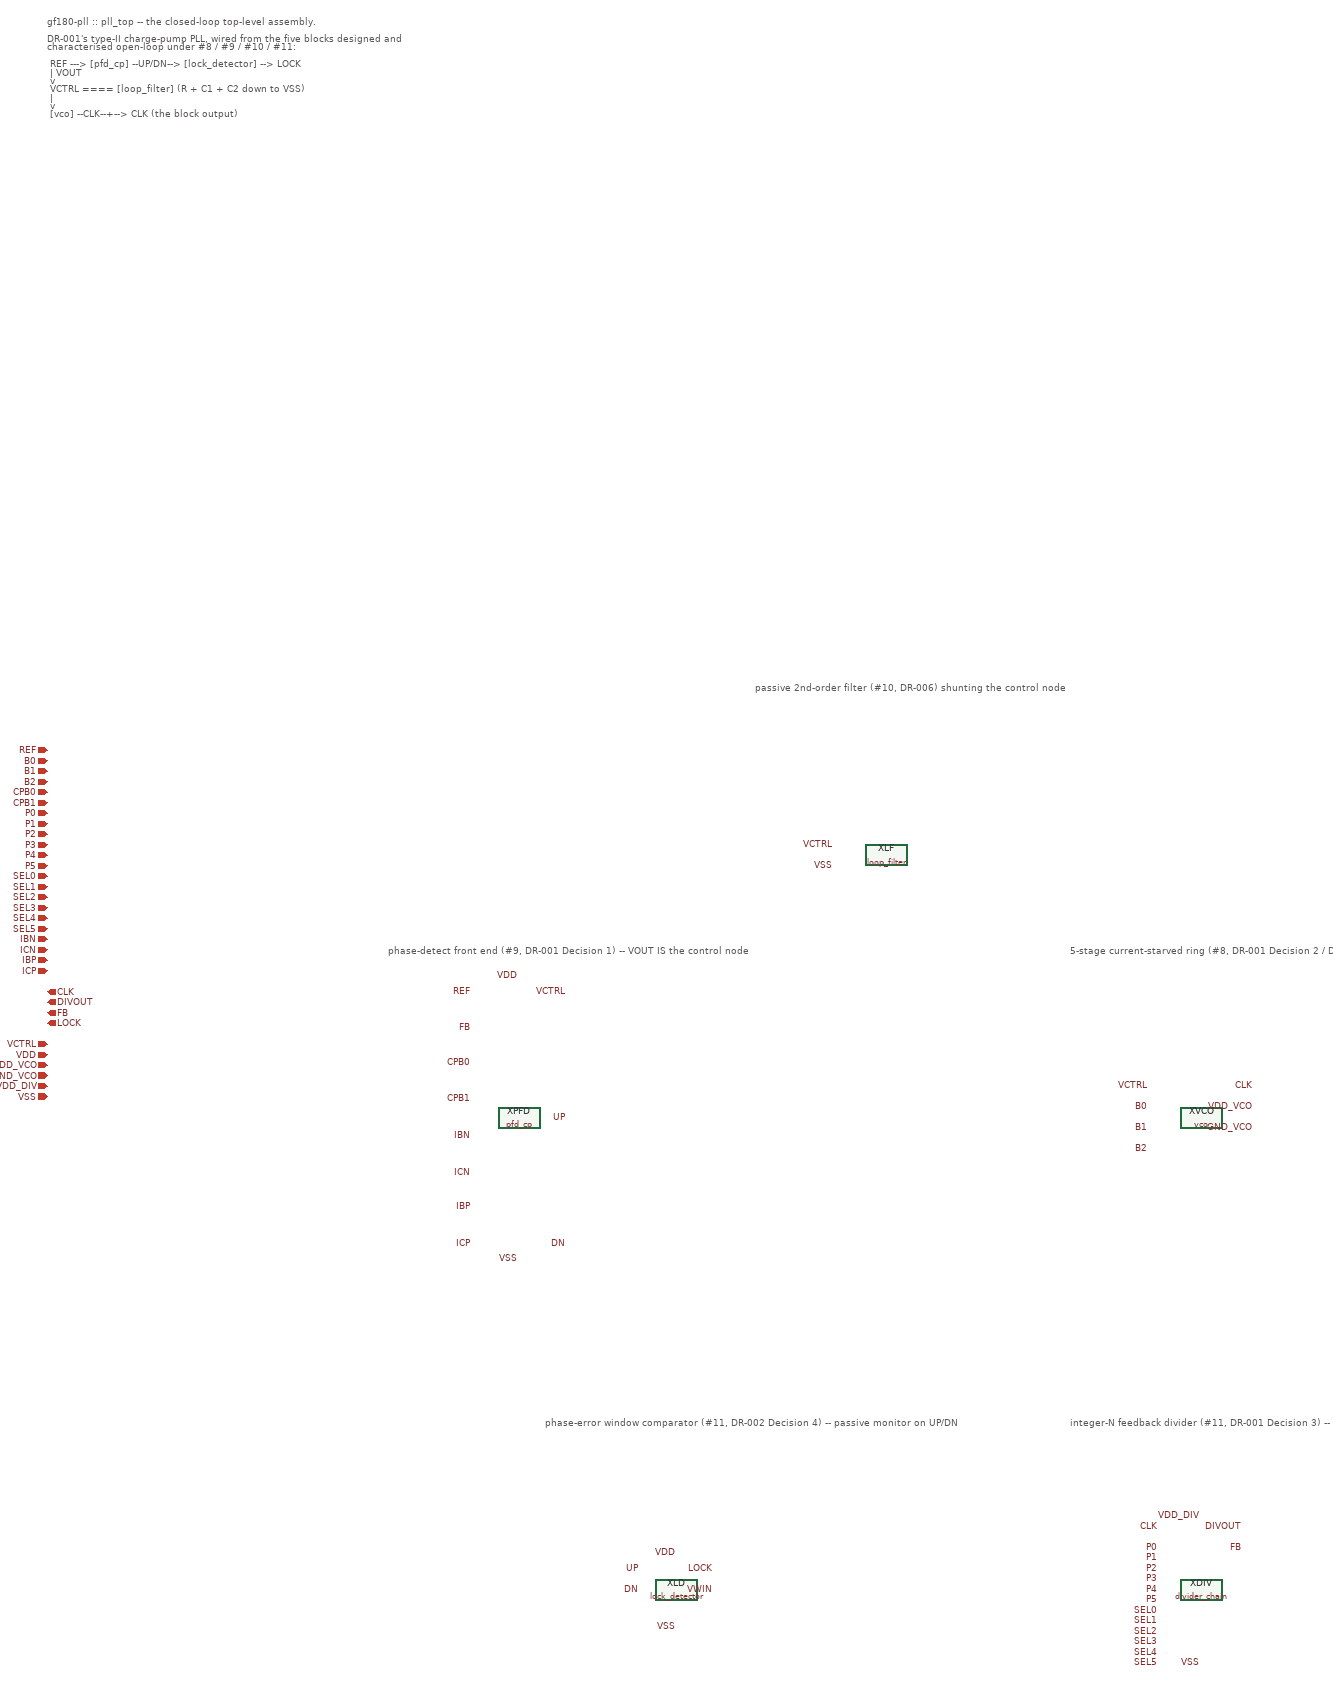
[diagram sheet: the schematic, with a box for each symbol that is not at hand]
v {xschem version=3.4.7 file_version=1.2}
G {}
K {}
V {}
S {}
E {}
T {gf180-pll :: pll_top -- the closed-loop top-level assembly.

DR-001's type-II charge-pump PLL, wired from the five blocks designed and
characterised open-loop under #8 / #9 / #10 / #11:

  REF ---> [pfd_cp] --UP/DN--> [lock_detector] --> LOCK
             | VOUT
             v
           VCTRL ==== [loop_filter]  (R + C1 + C2 down to VSS)
             |
             v
           [vco] --CLK--+--> CLK  (the block output)
                        |
                        v
               [divider_chain] --FB--> back to pfd_cp.FB
                        |
                        +--> DIVOUT (pre-retiming monitor tap)

Four wiring facts that are load-bearing, and where each comes from:

 1. pfd_cp.VOUT, loop_filter.VCTRL and vco.VCTRL are ONE net (VCTRL).  The
    loop filter is a two-terminal shunt network -- loop_filter.sym has
    exactly VCTRL and VSS -- because DR-001 Decision 1 puts it passively
    across the charge pump's output node.  There is no current-injection
    pin and nothing in series with the loop.

 2. pfd_cp.FB is driven by divider_chain.FB, NOT by divider_chain.DIVOUT.
    FB is the output of the retiming flop XFRT inside divider_chain, clocked
    by the VCO, so the edge the PFD sees is one flop clk->Q after a VCO edge
    INDEPENDENT of N -- DR-001 Decision 3's interface contract to #9.  DIVOUT
    is the raw chain/mux output, whose delay is the accumulated clk->Q of the
    k ACTIVE cells and therefore moves with the programmed N.  Wiring DIVOUT
    to the PFD would still lock, and a single-point smoke test would not
    notice, but it would reintroduce exactly the N-dependent static phase
    offset the retiming flop exists to remove.  Both are brought out as
    monitor pins so a testbench can see the retiming for itself.

 3. lock_detector taps UP and DN -- the PFD outputs -- not the control node.
    It is a passive monitor (DR-002 Decision 4): nothing in it drives a loop
    node.  Its VWIN pin is an OUTPUT (the integrating window node, brought
    out of the cell for observation), not a threshold input, so it stays an
    internal net here.

 4. Three supply domains stay separate all the way out to the pins:
    VDD (reference / PFD / charge pump / lock detector), VDD_VCO + GND_VCO
    (the VCO's own quiet domain, with its on-chip decap inside vco.sch) and
    VDD_DIV (the divider).  DR-001 Decisions 2 and 3.  VSS is the shared
    ground for everything except the VCO, which brings out its own GND_VCO.

Static configuration inputs -- the integrator drives all of them; there is no
calibration FSM in v1 (DR-001 Decision 2):

  B2 B1 B0      VCO coarse band select, 3-bit geometric map (see vco.sch)
  CPB1 CPB0     charge-pump Icp trim, 2-bit unit-element (see cp.sch).
                Named CPB* rather than B* only so the top-level net names stay
                distinct from the VCO band bits.
  P5..P0        divider modulus bits,  N = 2^k + sum(P_j . 2^j), j < k
  SEL5..SEL0    divider chain-length code, one-hot: SEL_(k-1) = 1

IBN / ICN / IBP / ICP are the charge pump's four current references.  Bias
generation is deliberately NOT part of this block (design/README.md: "Bias
generation is out of scope for this block"); testbenches drive them from
ideal sources at 4x the unit-leg current, exactly as sim/devchar-cp and
sim/pfd-deadzone do, so a measured result stays the loop's own and does not
fold in a bias generator that has not been designed yet.

Observability pins -- CLK, DIVOUT, FB, LOCK and VCTRL.  VCTRL is brought out
so a testbench can watch the control node, and force it for a bring-up sweep,
without reaching into the hierarchy; nothing external drives it in normal
closed-loop operation.

Netlist export: pll_top is a COMMITTED top (design/netlist.sh BLOCKS), so
design/netlist/pll_top.spice is regenerated by design/netlist.sh and checked
by design/netlist.sh --check.  sim/lib/pll_top_dut.sh is the helper that turns
that export into a runnable deck (sim/pll-top-smoke, sim/supply-sensitivity).
It is NOT yet the only closed-loop assembly path in the repo: sim/lock-time and
sim/output-range still build their DUT with sim/lib/assemble_closed_loop.sh,
which concatenates the individual block exports and never reads this file --
see sim/README.md, "Closed-loop campaigns: two assembly paths".} -900 -2100 0 0 0.4 0.4 {}
C {ipin.sym} -900 -700 0 0 {name=p_ref lab=REF}
C {ipin.sym} -900 -680 0 0 {name=p_b0 lab=B0}
C {ipin.sym} -900 -660 0 0 {name=p_b1 lab=B1}
C {ipin.sym} -900 -640 0 0 {name=p_b2 lab=B2}
C {ipin.sym} -900 -620 0 0 {name=p_cpb0 lab=CPB0}
C {ipin.sym} -900 -600 0 0 {name=p_cpb1 lab=CPB1}
C {ipin.sym} -900 -580 0 0 {name=p_p0 lab=P0}
C {ipin.sym} -900 -560 0 0 {name=p_p1 lab=P1}
C {ipin.sym} -900 -540 0 0 {name=p_p2 lab=P2}
C {ipin.sym} -900 -520 0 0 {name=p_p3 lab=P3}
C {ipin.sym} -900 -500 0 0 {name=p_p4 lab=P4}
C {ipin.sym} -900 -480 0 0 {name=p_p5 lab=P5}
C {ipin.sym} -900 -460 0 0 {name=p_sel0 lab=SEL0}
C {ipin.sym} -900 -440 0 0 {name=p_sel1 lab=SEL1}
C {ipin.sym} -900 -420 0 0 {name=p_sel2 lab=SEL2}
C {ipin.sym} -900 -400 0 0 {name=p_sel3 lab=SEL3}
C {ipin.sym} -900 -380 0 0 {name=p_sel4 lab=SEL4}
C {ipin.sym} -900 -360 0 0 {name=p_sel5 lab=SEL5}
C {ipin.sym} -900 -340 0 0 {name=p_ibn lab=IBN}
C {ipin.sym} -900 -320 0 0 {name=p_icn lab=ICN}
C {ipin.sym} -900 -300 0 0 {name=p_ibp lab=IBP}
C {ipin.sym} -900 -280 0 0 {name=p_icp lab=ICP}
C {opin.sym} -900 -240 0 0 {name=p_clk lab=CLK}
C {opin.sym} -900 -220 0 0 {name=p_divout lab=DIVOUT}
C {opin.sym} -900 -200 0 0 {name=p_fb lab=FB}
C {opin.sym} -900 -180 0 0 {name=p_lock lab=LOCK}
C {iopin.sym} -900 -140 0 0 {name=p_vctrl lab=VCTRL}
C {iopin.sym} -900 -120 0 0 {name=p_vdd lab=VDD}
C {iopin.sym} -900 -100 0 0 {name=p_vdd_vco lab=VDD_VCO}
C {iopin.sym} -900 -80 0 0 {name=p_gnd_vco lab=GND_VCO}
C {iopin.sym} -900 -60 0 0 {name=p_vdd_div lab=VDD_DIV}
C {iopin.sym} -900 -40 0 0 {name=p_vss lab=VSS}

T {phase-detect front end (#9, DR-001 Decision 1) -- VOUT IS the control node} -250 -330 0 0 0.4 0.4 {}
C {pfd_cp.sym} 0 0 0 0 {name=XPFD}
C {lab_pin.sym} -90 -240 0 0 {name=l_XPFD_REF lab=REF}
C {lab_pin.sym} -90 -170 0 0 {name=l_XPFD_FB lab=FB}
C {lab_pin.sym} -90 -105 0 0 {name=l_XPFD_B0 lab=CPB0}
C {lab_pin.sym} -90 -35 0 0 {name=l_XPFD_B1 lab=CPB1}
C {lab_pin.sym} -90 35 0 0 {name=l_XPFD_IBN lab=IBN}
C {lab_pin.sym} -90 105 0 0 {name=l_XPFD_ICN lab=ICN}
C {lab_pin.sym} -90 170 0 0 {name=l_XPFD_IBP lab=IBP}
C {lab_pin.sym} -90 240 0 0 {name=l_XPFD_ICP lab=ICP}
C {lab_pin.sym} 90 -240 0 0 {name=l_XPFD_VOUT lab=VCTRL}
C {lab_pin.sym} 90 0 0 0 {name=l_XPFD_UP lab=UP}
C {lab_pin.sym} 90 240 0 0 {name=l_XPFD_DN lab=DN}
C {lab_pin.sym} 0 -270 0 0 {name=l_XPFD_VDD lab=VDD}
C {lab_pin.sym} 0 270 0 0 {name=l_XPFD_VSS lab=VSS}

T {passive 2nd-order filter (#10, DR-006) shunting the control node} 450 -830 0 0 0.4 0.4 {}
C {loop_filter.sym} 700 -500 0 0 {name=XLF}
C {lab_pin.sym} 600 -520 0 0 {name=l_XLF_VCTRL lab=VCTRL}
C {lab_pin.sym} 600 -480 0 0 {name=l_XLF_VSS lab=VSS}

T {5-stage current-starved ring (#8, DR-001 Decision 2 / DR-003)} 1050 -330 0 0 0.4 0.4 {}
C {vco.sym} 1300 0 0 0 {name=XVCO}
C {lab_pin.sym} 1200 -60 0 0 {name=l_XVCO_VCTRL lab=VCTRL}
C {lab_pin.sym} 1200 -20 0 0 {name=l_XVCO_B0 lab=B0}
C {lab_pin.sym} 1200 20 0 0 {name=l_XVCO_B1 lab=B1}
C {lab_pin.sym} 1200 60 0 0 {name=l_XVCO_B2 lab=B2}
C {lab_pin.sym} 1400 -60 0 0 {name=l_XVCO_CLK lab=CLK}
C {lab_pin.sym} 1400 -20 0 0 {name=l_XVCO_VDD_VCO lab=VDD_VCO}
C {lab_pin.sym} 1400 20 0 0 {name=l_XVCO_GND_VCO lab=GND_VCO}

T {integer-N feedback divider (#11, DR-001 Decision 3) -- FB closes the loop, DIVOUT is a tap} 1050 570 0 0 0.4 0.4 {}
C {divider_chain.sym} 1300 900 0 0 {name=XDIV}
C {lab_pin.sym} 1220 780 0 0 {name=l_XDIV_VCO lab=CLK}
C {lab_pin.sym} 1220 820 0 0 {name=l_XDIV_P0 lab=P0}
C {lab_pin.sym} 1220 840 0 0 {name=l_XDIV_P1 lab=P1}
C {lab_pin.sym} 1220 860 0 0 {name=l_XDIV_P2 lab=P2}
C {lab_pin.sym} 1220 880 0 0 {name=l_XDIV_P3 lab=P3}
C {lab_pin.sym} 1220 900 0 0 {name=l_XDIV_P4 lab=P4}
C {lab_pin.sym} 1220 920 0 0 {name=l_XDIV_P5 lab=P5}
C {lab_pin.sym} 1220 940 0 0 {name=l_XDIV_SEL0 lab=SEL0}
C {lab_pin.sym} 1220 960 0 0 {name=l_XDIV_SEL1 lab=SEL1}
C {lab_pin.sym} 1220 980 0 0 {name=l_XDIV_SEL2 lab=SEL2}
C {lab_pin.sym} 1220 1000 0 0 {name=l_XDIV_SEL3 lab=SEL3}
C {lab_pin.sym} 1220 1020 0 0 {name=l_XDIV_SEL4 lab=SEL4}
C {lab_pin.sym} 1220 1040 0 0 {name=l_XDIV_SEL5 lab=SEL5}
C {lab_pin.sym} 1380 780 0 0 {name=l_XDIV_DIVOUT lab=DIVOUT}
C {lab_pin.sym} 1380 820 0 0 {name=l_XDIV_FB lab=FB}
C {lab_pin.sym} 1300 760 0 0 {name=l_XDIV_VDD_DIV lab=VDD_DIV}
C {lab_pin.sym} 1300 1040 0 0 {name=l_XDIV_VSS lab=VSS}

T {phase-error window comparator (#11, DR-002 Decision 4) -- passive monitor on UP/DN} 50 570 0 0 0.4 0.4 {}
C {lock_detector.sym} 300 900 0 0 {name=XLD}
C {lab_pin.sym} 230 860 0 0 {name=l_XLD_UP lab=UP}
C {lab_pin.sym} 230 900 0 0 {name=l_XLD_DN lab=DN}
C {lab_pin.sym} 370 860 0 0 {name=l_XLD_LOCK lab=LOCK}
C {lab_pin.sym} 370 900 0 0 {name=l_XLD_VWIN lab=VWIN}
C {lab_pin.sym} 300 830 0 0 {name=l_XLD_VDD lab=VDD}
C {lab_pin.sym} 300 970 0 0 {name=l_XLD_VSS lab=VSS}
